One B-rep face of a CAD part: STEP entity #289.
In plain terms, the planar face has unit normal (-1, 0, 0).
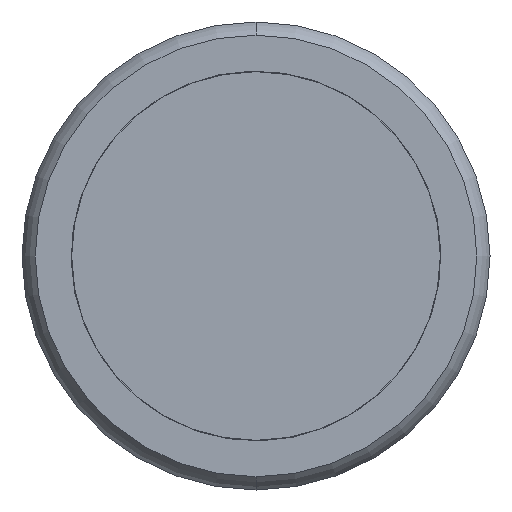
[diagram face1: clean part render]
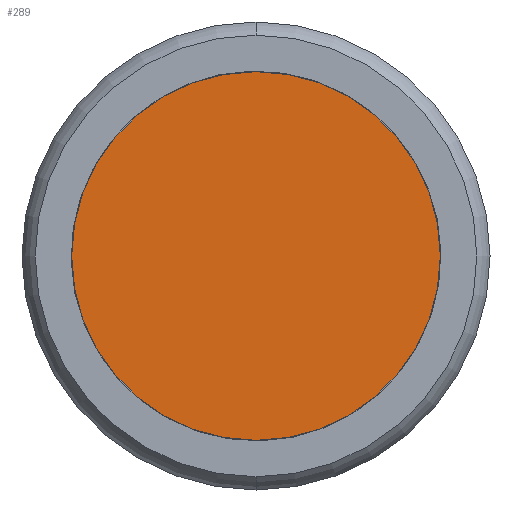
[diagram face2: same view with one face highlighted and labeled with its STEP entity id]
Its self-contained STEP definition (entity closure, numbers rounded to 3 decimals):
#228 = EDGE_CURVE ( 'NONE', #402, #359, #1542, .T. ) ;
#247 = EDGE_CURVE ( 'NONE', #359, #402, #1580, .T. ) ;
#289 = ADVANCED_FACE ( 'NONE', ( #2034 ), #2038, .F. ) ;
#359 = VERTEX_POINT ( 'NONE', #3627 ) ;
#363 = ORIENTED_EDGE ( 'NONE', *, *, #228, .F. ) ;
#402 = VERTEX_POINT ( 'NONE', #3697 ) ;
#626 = EDGE_LOOP ( 'NONE', ( #363, #963 ) ) ;
#963 = ORIENTED_EDGE ( 'NONE', *, *, #247, .F. ) ;
#1387 = CARTESIAN_POINT ( 'NONE',  ( 0.374, 0., 0. ) ) ;
#1390 = DIRECTION ( 'NONE',  ( 1., 0., 0. ) ) ;
#1418 = DIRECTION ( 'NONE',  ( 0., 1., 0. ) ) ;
#1461 = DIRECTION ( 'NONE',  ( 0., 1., 0. ) ) ;
#1464 = CARTESIAN_POINT ( 'NONE',  ( 0.374, 0., 0. ) ) ;
#1478 = DIRECTION ( 'NONE',  ( 1., 0., 0. ) ) ;
#1508 = AXIS2_PLACEMENT_3D ( 'NONE', #1387, #1390, #1418 ) ;
#1542 = CIRCLE ( 'NONE', #1508, 1.58 ) ;
#1580 = CIRCLE ( 'NONE', #1587, 1.58 ) ;
#1587 = AXIS2_PLACEMENT_3D ( 'NONE', #1464, #1478, #1461 ) ;
#1646 = AXIS2_PLACEMENT_3D ( 'NONE', #2036, #2026, #1989 ) ;
#1989 = DIRECTION ( 'NONE',  ( 0., 1., 0. ) ) ;
#2026 = DIRECTION ( 'NONE',  ( 1., 0., 0. ) ) ;
#2034 = FACE_OUTER_BOUND ( 'NONE', #626, .T. ) ;
#2036 = CARTESIAN_POINT ( 'NONE',  ( 0.374, 1.735, -10. ) ) ;
#2038 = PLANE ( 'NONE',  #1646 ) ;
#3627 = CARTESIAN_POINT ( 'NONE',  ( 0.374, 0., -1.58 ) ) ;
#3697 = CARTESIAN_POINT ( 'NONE',  ( 0.374, 0., 1.58 ) ) ;
